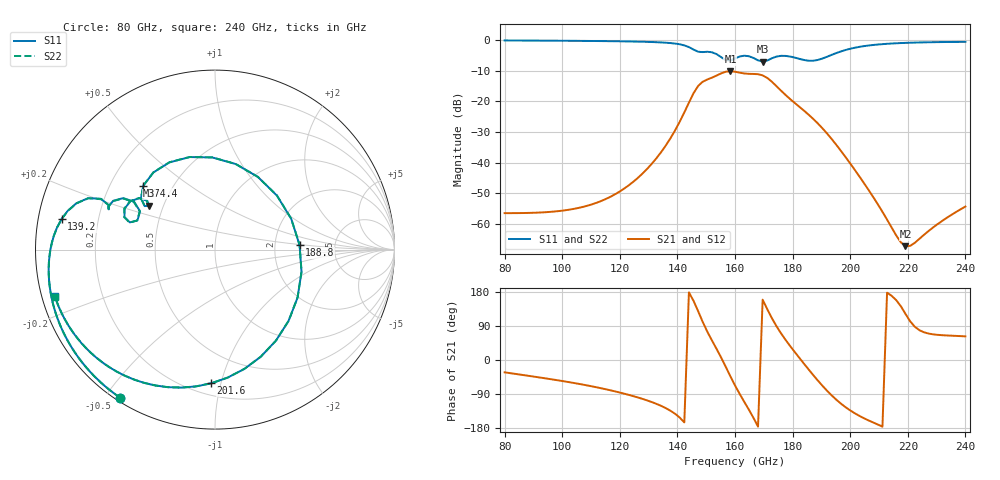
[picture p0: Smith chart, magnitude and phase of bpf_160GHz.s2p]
#  GHZ S DB R 50
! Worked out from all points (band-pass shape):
!   101 points, 80 GHz to 240 GHz, reference 50 ohm
!   highest |S21| = -10.20 dB at 158.4 GHz (marker M1); lowest = -67.3 dB at 219.2 GHz (marker M2)
!   |S21| within 3 dB of the highest: 149.7 GHz to 172.2 GHz (22.5 GHz wide, 14 % of centre)
!   lowest |S11| = -7.1 dB at 169.6 GHz (marker M3), VSWR 2.58, Z = 20.8 + j12.6 ohm
!   |S11| at or under -10 dB: nowhere
!   |S22| runs from -7.0 to -0.2 dB; largest |S21 - S12| = 4.8e-13
!   S11 on the Smith chart (normalised r, x): 80 GHz: 0.01, -0.55; 139.2 GHz: 0.07, +0.10; 174.4 GHz: 0.34, +0.34; 188.8 GHz: 2.77, +0.18; 201.6 GHz: 0.28, -0.93; 240 GHz: 0.04, -0.14
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80  -0.18 -122.7  -56.48 -32.5  -56.48 -32.5  -0.18 -122.6
107.2  -0.32 -150.2  -54.45 -65.0  -54.45 -65.0  -0.32 -150.2
121.6  -0.48 -165.5  -48.43 -89.0  -48.43 -89.0  -0.48 -165.4
134.4  -0.82 177.5  -36.52 -121.2  -36.52 -121.2  -0.82 177.5
139.2  -1.19 168.8  -29.49 -142.0  -29.49 -142.0  -1.20 168.7
144  -2.34 158.0  -20.45 178.5  -20.45 178.5  -2.37 158.0
147.2  -3.86 157.3  -15.00 128.7  -15.00 128.7  -3.89 157.5
150.4  -3.86 158.0  -12.90 74.5  -12.90 74.5  -3.87 158.3
155.2  -5.62 149.4  -10.90 6.3  -10.90 6.3  -5.60 149.6
158.4  -6.71 159.4  -10.20 -43.1  -10.20 -43.1  -6.68 159.6
160  -6.05 162.3  -10.37 -67.1  -10.37 -67.1  -6.03 162.4
166.4  -5.88 145.7  -11.09 -152.5  -11.09 -152.5  -5.82 145.8
169.6  -7.10 146.5  -11.56 159.2  -11.56 159.2  -7.02 146.3
174.4  -5.43 138.2  -15.08 89.3  -15.08 89.3  -5.42 137.9
180.8  -5.79 91.7  -20.61 20.6  -20.61 20.6  -5.78 91.6
187.2  -6.78 21.9  -25.79 -40.1  -25.79 -40.1  -6.78 22.2
188.8  -6.52 3.1  -27.27 -54.5  -27.27 -54.5  -6.53 3.4
195.2  -4.28 -56.4  -34.24 -104.9  -34.24 -104.9  -4.29 -56.1
201.6  -2.55 -91.7  -42.39 -140.7  -42.39 -140.7  -2.57 -91.4
214.4  -1.18 -129.0  -61.20 169.3  -61.20 169.3  -1.19 -128.8
219.2  -0.97 -137.8  -67.25 121.6  -67.25 121.6  -0.98 -137.6
240  -0.63 -163.7  -54.34 62.4  -54.34 62.4  -0.64 -163.5
